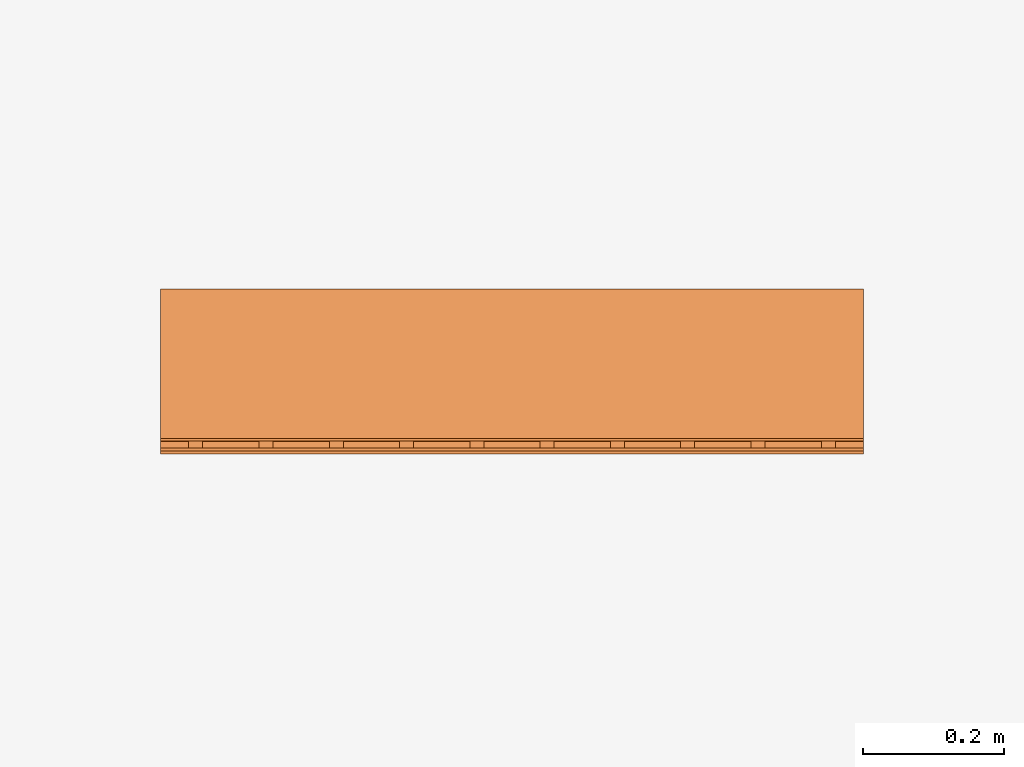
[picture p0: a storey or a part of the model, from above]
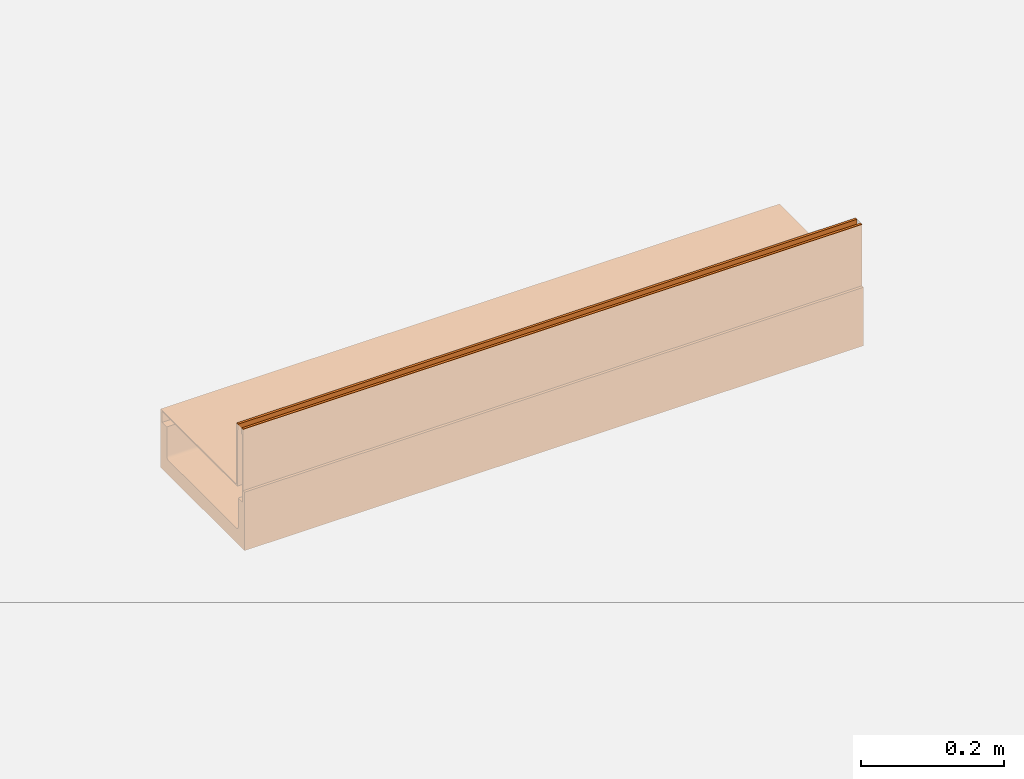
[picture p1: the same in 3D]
Properties of the parts of a building model (IFC2X3)

# File
Description: ViewDefinition [CoordinationView]
File name: 23216 - No 0100 Constant Depth Channel - 1000mm LG - Invert Depth 75mm.ifc
Time: 2013-10-30T13:49:01
Written by: Autodesk Revit 2013
Made in: 20120221_2030(x64)

# IfcProject, Project Number
LongName: Project Name; Phase: Project Status

# IfcSite, Default
RefLatitude: 42, 21, 30, 344238; RefLongitude: -71, -3, -35, -194702; RefElevation: 0 mm

# IfcBuilding
Pset_BuildingCommon - NumberOfStoreys: 1
Other - Project Address: ## Street City, State Zip; Project Status: Project Status; Project Number: Project Number; Project Issue Date: Issue Date; Project Name: Project Name; Client Name: Owner

# IfcBuildingStorey, Level 1
LongName: Level 1; Elevation: 0 mm
Constraints - Elevation Base: 0; Elevation: 0 mm
Graphics - Symbol at End 2 Default: yes; Symbol: M_Level Head - Circle: M_Level Head - Circle; Line Pattern: Center; Symbol at End 1 Default: no; Line Weight: 1; Color: 0
Dimensions - Computation Height: 0 mm
Identity Data - Name: Level 1; Building Story: yes; Structural: no

# IfcBuildingElementProxy: 23216 - No 0100 Constant Depth Channel - 1000mm LG - Invert Depth 75mm, Civil-Drainage-Channel-ACO-MultiDrain-M200D-Brickslot-Channel-System:23216 - No 0100 Constant Depth Channel - 1000mm LG - Invert Depth 75mm:23216 - No 0100 Constant Depth Channel - 1000mm LG - Invert Depth 75mm:196059
In: Level 1
Material: Steel, Galvanized, Vienite® Synthetic Resin Concrete
Constraints - Level: Level: Level 1; Moves With Nearby Elements: no
Dimensions - EndCap Position: 1000 mm; Brickslot Access Unit Void Bottom Depth: -6105 mm; Brickslot Grating Void Depth: 0 mm; Volume: 9199297 mm3; FloorCut_Length: -1000 mm; Brickslot Access Void Depth: -6000 mm; Brickslot Void Length: -1000 mm; Custom_Void_Length: 0 mm; Length: 1000 mm; FloorCut_Width: 235 mm; Brickslot Access unit void length: -500 mm; FloorCut_Depth: 100 mm; EndCap_Height: 100 mm; Depth: 365 mm; InvDepth: 240 mm; FloorCut_HorPosition: 117.5 mm; Length Drain: -1000 mm
Construction - 408997_Load Class C250 & D400_Brickslot_Access Unit_Galvanized Steel_500mm Long: no; 23219 - Universal Endcap (Male End): no; 23219 - Universal Endcap (Female End): no; 408996_Load Class C250 & D400_Brickslot Grating_Galvanized Steel_500mm Long: no; 408995_Load Class C250 & D400_Brickslot Grating_Galvanized Steel_1000mm Long: yes; 23410_Sump Unit: no; Constant Depth Channel_500: no; Shallow Depth Channel: yes; Shallow Depth Channel with seal: no; Constant Depth Channel_1000: no
Phasing - Phase Created: New Construction
Pset_BuildingElementProxyCommon - Reference: 23216 - No 0100 Constant Depth Channel - 1000mm LG - Invert Depth 75mm
Identity Data - Assembly Code: D2040; Address: ACO Business Park, Hitchin Road, Shefford, Bedfordshire, United Kingdom SG17 5TE; Cost: 0; e-mail Technical: technical@aco.co.uk; Product Code: 23216; Fax: +44 (0)1462 815895; OmniClass Number: 23.70.50.24; Telephone: +44 (0)1462 816666; Watermark 1: This file is the property of ACO Technologies PLC; Manufacturer: ACO Technologies plc - ACO Water Management Division; Assembly Description: Rain Water Drainage; Watermarked With: BIM Manager Premium Suite; Product brochure: http://www.aco.co.uk/download.php?id=173; Product Page URL: http://www.aco.co.uk/product_detail.php?id=58; Installation guidelines: http://www.aco.co.uk/download.php?id=173; e-mail Sales: customersupport@aco.co.uk; Watermarked By: www.aco.co.uk; Model Description: Channel drainage system; Watermark 2: This file is water marked and users are prohibited to reproduce, adapt, distribute this information; Price: POA - contact ACO; URL: www.aco.co.uk; Maintenance guidelines: http://www.aco.co.uk/download.php?id=173; OmniClass Title: Rainwater Removal; Model: ACO MultiDrain MD Brickslot - M200D; Type Comments: ACO MultiDrain M200D 0100 Shallow Constant Depth Channel 1000mm Long
Data - Installation - Concrete Grade: Refer to brochure; Load Class: A 15 - D 400; Concrete Surround Volume - Load Class A 15 - Concrete Pavement: 0.06m³/m; Product Standard: BS EN 1433:2002, CE marked; Hydraulic Performance: http://www.aco.co.uk/download.php?id=173; Pre-formed Outlet Ø: N/A; Concrete Surround Volume - Load Class D 400 - Concrete Pavement: 0.17m³/m; Channel C.S.A: 0.01m²; Product Weight: 17.5Kg; Invert Depth: 75mm; Product Dimensions: 1000mm x 235mm x 100mm (LxWxH); ACO Hydraulic Design Software: http://www.acodesign.co.uk; Concrete Surround Volume - Load Class B 125 - C 250 - Concrete Pavement: 0.11m³/m
Green Building Properties - Channel Recycled Material Content: 20% minimum; Channel Recyclable: Fully recyclable; Edge Rail Recycled Material Content: Between 40% - 90%; Edge Rail Recyclable: Fully recyclable
General - TagNumber: 0; SerialNumber: 0
Materials and Finishes - Edge Rail Colour: Silver; Edge Rail Finish: Pre-galvanised; Channel Material: Vienite® Synthetic Resin Concrete; Edge Rail Material: Steel; Channel Colour: Brown
Other - CreatedBy: www.aco.co.uk; Revision: 1
Model Properties - Brickslot Grating Product code 408995: Load Class C250/D400 - Brickslot Galvanized Steel - 1000mm long x 105mm high - 10mm Slot - Intake area - 10000mm²/m - 9.8kg; Brickslot Grating Product code 408996: Load Class C250/D400 - Brickslot Galvanized Steel - 500mm long x 105mm high - 10mm Slot - Intake area - 10000mm²/m - 4.8kg; End Cap Product code 23219: No. 306 Universal End Cap - 235mm wide x 365mm long - Spigot Ø160mm x 75mm long - Silver - Polypropylene - 0.4kg; Brickslot Access Unit Product code 408997: Load Class C250/D400 - Brickslot Access Unit Galvanised Steel - 500mm long x 105mm high - 10mm Slot - Intake area - 10000mm²/m 8.5 Kg

# IfcOpeningElement: Recess (2)
In: Level 1
Structural - Enable Analytical Model: no; Structural: no
Dimensions - Area: 25000000 mm2; Thickness: 400 mm; Perimeter: 20000 mm; Volume: 9974610000 mm3
Constraints - Height Offset From Level: 0 mm; Room Bounding: yes; Related to Mass: no; Level: Level: Level 1
Phasing - Phase Created: New Construction
Analytical Properties - Thermal Resistance (R): 0.477897; Heat Transfer Coefficient (U): 2.0925; Roughness: 1; Absorptance: 0.1; Thermal mass: 543920
Construction - Function: 0; Default Thickness: 400 mm
Materials and Finishes - Structural Material: Earth
Graphics - Coarse Scale Fill Color: 0

# IfcSlab: Floor:Generic Floor - 400mm, Floor:Generic Floor - 400mm:193825
In: Level 1
PredefinedType: FLOOR; Material: Earth 400 mm
Structural - Enable Analytical Model: no; Structural: no
Dimensions - Area: 25000000 mm2; Thickness: 400 mm; Perimeter: 20000 mm; Volume: 9974610000 mm3
Constraints - Height Offset From Level: 0 mm; Room Bounding: yes; Related to Mass: no; Level: Level: Level 1
Phasing - Phase Created: New Construction
Pset_SlabCommon - Reference: Generic Floor - 400mm; IsExternal: no; LoadBearing: yes
Analytical Properties - Thermal Resistance (R): 0.477897; Heat Transfer Coefficient (U): 2.0925; Roughness: 1; Absorptance: 0.1; Thermal mass: 543920
Construction - Function: 0; Default Thickness: 400 mm
Materials and Finishes - Structural Material: Earth
Graphics - Coarse Scale Fill Color: 0
